VERSION 5.7 ;
  NOWIREEXTENSIONATPIN ON ;
  DIVIDERCHAR "/" ;
  BUSBITCHARS "[]" ;
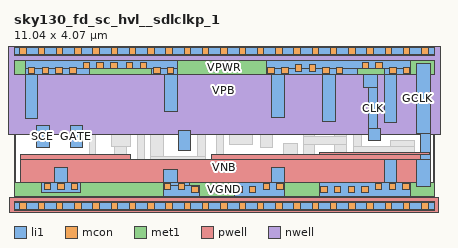
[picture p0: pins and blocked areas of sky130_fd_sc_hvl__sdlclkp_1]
MACRO sky130_fd_sc_hvl__sdlclkp_1
  CLASS BLOCK ;
  FOREIGN sky130_fd_sc_hvl__sdlclkp_1 ;
  ORIGIN 0.000 0.000 ;
  SIZE 11.040 BY 4.070 ;
  PIN CLK
    ANTENNAGATEAREA 1.170000 ;
    PORT
      LAYER li1 ;
        RECT 9.195 3.125 9.560 3.445 ;
        RECT 9.310 2.025 9.560 3.125 ;
        RECT 4.320 1.465 4.650 1.975 ;
        RECT 9.310 1.725 9.640 2.025 ;
    END
  END CLK
  PIN GATE
    ANTENNAGATEAREA 0.585000 ;
    PORT
      LAYER li1 ;
        RECT 1.475 1.535 1.805 2.125 ;
    END
  END GATE
  PIN SCE
    ANTENNAGATEAREA 0.585000 ;
    PORT
      LAYER li1 ;
        RECT 0.595 1.535 0.925 2.125 ;
    END
  END SCE
  PIN VGND
    USE GROUND ;
    PORT
      LAYER li1 ;
        RECT 1.070 0.625 1.400 1.025 ;
        RECT 3.940 0.625 4.290 0.955 ;
        RECT 6.780 0.625 7.110 1.025 ;
        RECT 9.730 0.625 10.060 1.215 ;
        RECT 0.730 0.365 1.740 0.625 ;
        RECT 3.940 0.535 4.610 0.625 ;
        RECT 3.940 0.255 4.885 0.535 ;
        RECT 5.790 0.255 7.110 0.625 ;
        RECT 8.040 0.255 10.420 0.625 ;
      LAYER mcon ;
        RECT 0.790 0.425 0.960 0.595 ;
        RECT 1.150 0.425 1.320 0.595 ;
        RECT 1.510 0.425 1.680 0.595 ;
        RECT 3.955 0.425 4.125 0.595 ;
        RECT 4.315 0.425 4.485 0.595 ;
        RECT 4.675 0.355 4.845 0.525 ;
        RECT 5.830 0.355 6.000 0.525 ;
        RECT 6.190 0.355 6.360 0.525 ;
        RECT 6.550 0.425 6.720 0.595 ;
        RECT 6.910 0.425 7.080 0.595 ;
        RECT 8.060 0.355 8.230 0.525 ;
        RECT 8.420 0.355 8.590 0.525 ;
        RECT 8.780 0.355 8.950 0.525 ;
        RECT 9.140 0.355 9.310 0.525 ;
        RECT 9.500 0.425 9.670 0.595 ;
        RECT 9.860 0.425 10.030 0.595 ;
        RECT 10.220 0.425 10.390 0.595 ;
      LAYER met1 ;
        RECT 0.000 0.255 11.040 0.625 ;
    END
  END VGND
  PIN VNB
    ANTENNADIFFAREA 1.876800 ;
    PORT
      LAYER pwell ;
        RECT 9.640 1.405 10.930 1.415 ;
        RECT 8.020 1.345 10.930 1.405 ;
        RECT 0.160 1.210 3.050 1.345 ;
        RECT 5.200 1.210 10.930 1.345 ;
        RECT 0.160 0.215 10.930 1.210 ;
        RECT -0.130 -0.215 11.170 0.215 ;
      LAYER li1 ;
        RECT 0.000 -0.085 11.040 0.085 ;
      LAYER mcon ;
        RECT 0.155 -0.085 0.325 0.085 ;
        RECT 0.635 -0.085 0.805 0.085 ;
        RECT 1.115 -0.085 1.285 0.085 ;
        RECT 1.595 -0.085 1.765 0.085 ;
        RECT 2.075 -0.085 2.245 0.085 ;
        RECT 2.555 -0.085 2.725 0.085 ;
        RECT 3.035 -0.085 3.205 0.085 ;
        RECT 3.515 -0.085 3.685 0.085 ;
        RECT 3.995 -0.085 4.165 0.085 ;
        RECT 4.475 -0.085 4.645 0.085 ;
        RECT 4.955 -0.085 5.125 0.085 ;
        RECT 5.435 -0.085 5.605 0.085 ;
        RECT 5.915 -0.085 6.085 0.085 ;
        RECT 6.395 -0.085 6.565 0.085 ;
        RECT 6.875 -0.085 7.045 0.085 ;
        RECT 7.355 -0.085 7.525 0.085 ;
        RECT 7.835 -0.085 8.005 0.085 ;
        RECT 8.315 -0.085 8.485 0.085 ;
        RECT 8.795 -0.085 8.965 0.085 ;
        RECT 9.275 -0.085 9.445 0.085 ;
        RECT 9.755 -0.085 9.925 0.085 ;
        RECT 10.235 -0.085 10.405 0.085 ;
        RECT 10.715 -0.085 10.885 0.085 ;
      LAYER met1 ;
        RECT 0.000 -0.115 11.040 0.115 ;
    END
  END VNB
  PIN VPB
    ANTENNADIFFAREA 1.876800 ;
    PORT
      LAYER nwell ;
        RECT -0.330 1.885 11.370 4.485 ;
      LAYER li1 ;
        RECT 0.000 3.985 11.040 4.155 ;
      LAYER mcon ;
        RECT 0.155 3.985 0.325 4.155 ;
        RECT 0.635 3.985 0.805 4.155 ;
        RECT 1.115 3.985 1.285 4.155 ;
        RECT 1.595 3.985 1.765 4.155 ;
        RECT 2.075 3.985 2.245 4.155 ;
        RECT 2.555 3.985 2.725 4.155 ;
        RECT 3.035 3.985 3.205 4.155 ;
        RECT 3.515 3.985 3.685 4.155 ;
        RECT 3.995 3.985 4.165 4.155 ;
        RECT 4.475 3.985 4.645 4.155 ;
        RECT 4.955 3.985 5.125 4.155 ;
        RECT 5.435 3.985 5.605 4.155 ;
        RECT 5.915 3.985 6.085 4.155 ;
        RECT 6.395 3.985 6.565 4.155 ;
        RECT 6.875 3.985 7.045 4.155 ;
        RECT 7.355 3.985 7.525 4.155 ;
        RECT 7.835 3.985 8.005 4.155 ;
        RECT 8.315 3.985 8.485 4.155 ;
        RECT 8.795 3.985 8.965 4.155 ;
        RECT 9.275 3.985 9.445 4.155 ;
        RECT 9.755 3.985 9.925 4.155 ;
        RECT 10.235 3.985 10.405 4.155 ;
        RECT 10.715 3.985 10.885 4.155 ;
      LAYER met1 ;
        RECT 0.000 3.955 11.040 4.185 ;
    END
  END VPB
  PIN VPWR
    USE POWER ;
    PORT
      LAYER li1 ;
        RECT 0.290 3.615 4.290 3.815 ;
        RECT 0.290 3.445 1.985 3.615 ;
        RECT 3.625 3.445 4.290 3.615 ;
        RECT 6.645 3.615 10.420 3.815 ;
        RECT 6.645 3.445 9.025 3.615 ;
        RECT 9.730 3.445 10.420 3.615 ;
        RECT 0.290 2.295 0.620 3.445 ;
        RECT 3.960 2.485 4.290 3.445 ;
        RECT 6.780 2.330 7.110 3.445 ;
        RECT 8.110 2.225 8.440 3.445 ;
        RECT 9.730 2.195 10.060 3.445 ;
      LAYER mcon ;
        RECT 0.380 3.475 0.550 3.645 ;
        RECT 0.740 3.475 0.910 3.645 ;
        RECT 1.100 3.475 1.270 3.645 ;
        RECT 1.460 3.475 1.630 3.645 ;
        RECT 1.820 3.615 1.990 3.785 ;
        RECT 2.180 3.615 2.350 3.785 ;
        RECT 2.540 3.615 2.710 3.785 ;
        RECT 2.955 3.615 3.125 3.785 ;
        RECT 3.315 3.615 3.485 3.785 ;
        RECT 3.675 3.475 3.845 3.645 ;
        RECT 4.035 3.475 4.205 3.645 ;
        RECT 6.675 3.475 6.845 3.645 ;
        RECT 7.035 3.475 7.205 3.645 ;
        RECT 7.395 3.545 7.565 3.715 ;
        RECT 7.755 3.545 7.925 3.715 ;
        RECT 8.115 3.475 8.285 3.645 ;
        RECT 8.475 3.475 8.645 3.645 ;
        RECT 9.155 3.615 9.325 3.785 ;
        RECT 9.515 3.615 9.685 3.785 ;
        RECT 9.875 3.475 10.045 3.645 ;
        RECT 10.235 3.475 10.405 3.645 ;
      LAYER met1 ;
        RECT 0.000 3.445 11.040 3.815 ;
    END
  END VPWR
  PIN GCLK
    ANTENNADIFFAREA 0.596250 ;
    PORT
      LAYER li1 ;
        RECT 10.590 1.895 10.955 3.735 ;
        RECT 10.685 1.215 10.955 1.895 ;
        RECT 10.590 0.515 10.955 1.215 ;
    END
  END GCLK
  OBS
      LAYER li1 ;
        RECT 2.155 3.225 3.455 3.445 ;
        RECT 1.850 2.295 2.145 3.055 ;
        RECT 1.975 1.365 2.145 2.295 ;
        RECT 2.630 1.885 2.960 3.055 ;
        RECT 3.235 2.315 3.455 3.225 ;
        RECT 4.480 3.385 6.475 3.555 ;
        RECT 4.480 2.315 4.650 3.385 ;
        RECT 3.235 2.145 4.650 2.315 ;
        RECT 4.820 3.005 6.135 3.215 ;
        RECT 2.555 1.555 3.065 1.885 ;
        RECT 0.290 1.195 2.145 1.365 ;
        RECT 0.290 0.840 0.620 1.195 ;
        RECT 1.850 0.840 2.145 1.195 ;
        RECT 2.630 0.840 2.960 1.555 ;
        RECT 3.235 1.080 3.430 2.145 ;
        RECT 3.180 0.705 3.430 1.080 ;
        RECT 3.600 1.295 3.930 1.965 ;
        RECT 4.820 1.295 5.030 3.005 ;
        RECT 3.600 1.125 5.030 1.295 ;
        RECT 2.115 0.535 2.825 0.670 ;
        RECT 3.600 0.535 3.770 1.125 ;
        RECT 4.780 0.705 5.030 1.125 ;
        RECT 5.335 2.330 5.620 2.660 ;
        RECT 6.305 2.595 6.475 3.385 ;
        RECT 6.095 2.425 6.475 2.595 ;
        RECT 5.335 1.365 5.505 2.330 ;
        RECT 6.095 1.945 6.265 2.425 ;
        RECT 7.620 2.085 7.890 2.660 ;
        RECT 5.675 1.615 6.265 1.945 ;
        RECT 6.475 1.875 7.890 2.085 ;
        RECT 6.475 1.535 6.805 1.875 ;
        RECT 7.620 1.825 7.890 1.875 ;
        RECT 8.415 1.825 8.745 2.055 ;
        RECT 7.085 1.365 7.450 1.655 ;
        RECT 5.335 1.195 7.450 1.365 ;
        RECT 5.335 0.535 5.620 1.195 ;
        RECT 2.115 0.365 3.770 0.535 ;
        RECT 5.055 0.255 5.620 0.535 ;
        RECT 7.280 0.670 7.450 1.195 ;
        RECT 7.620 1.615 8.745 1.825 ;
        RECT 7.620 0.840 7.890 1.615 ;
        RECT 8.415 1.385 8.745 1.615 ;
        RECT 8.915 1.555 9.140 2.955 ;
        RECT 9.905 1.555 10.515 1.725 ;
        RECT 8.915 1.385 10.515 1.555 ;
        RECT 8.915 1.215 9.140 1.385 ;
        RECT 8.110 0.885 9.140 1.215 ;
        RECT 7.280 0.355 7.870 0.670 ;
  END
END sky130_fd_sc_hvl__sdlclkp_1
END LIBRARY

